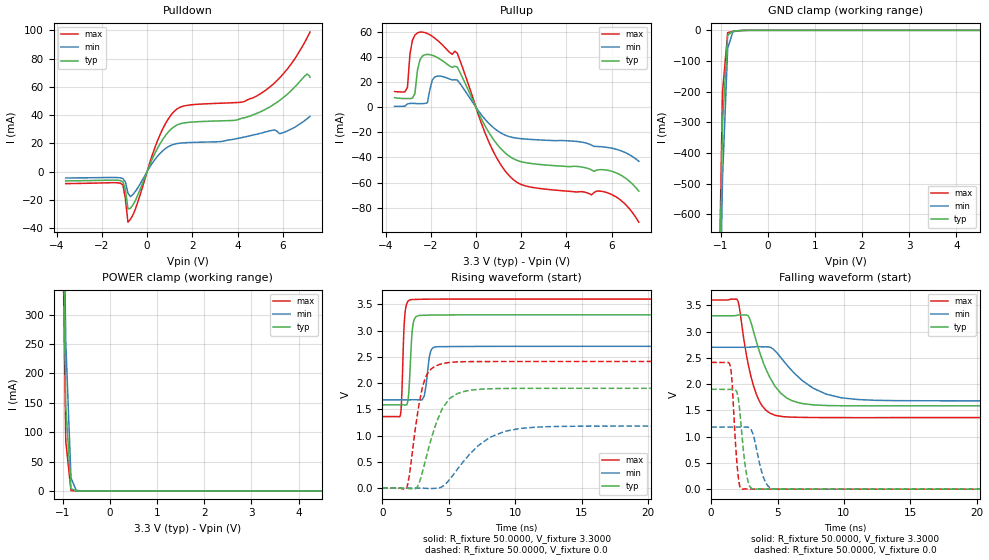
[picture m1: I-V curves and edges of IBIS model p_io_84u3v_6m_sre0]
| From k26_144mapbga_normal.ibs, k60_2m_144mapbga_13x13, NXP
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[Model] p_io_84u3v_6m_sre0
|   Model p_io_84u3v_6m_sre0
| Library cells for typ/min/max conditions are connected as defined below:
|  pad - External Pad
|  ipp_do - Core Input
|  ipp_obe - Output Buffer Enable
|  esd_boost - vdd_s_3v
|  esd_bus - vdd_s_3v
|  ipp_ina40a_3v - NC
|  ipp_ina40b_3v - NC
|  ipp_ina_3v - NC
|  ipp_ind - NC
|  ipp_ind_3v - NC
|  vdd_s_3v - vdd_s_3v
|  vdd_s_lv - vdd_s_lv
|  vss_bulk - vss_bulk
|  vss_s_lv - vss_s_lv
| All other pins connected to ground
Model_type I/O
Polarity   Non-Inverting
Enable   Active-High
Vinl =   1.1550V
Vinh =   2.3100V
Vmeas =  1.6500V
Cref =   25.0000pF
Rref =   50.0000
Vref =   0.0V
C_comp   2.2252pF   2.0533pF   2.4409pF
[Temperature Range]   25.0000   0.1250k   -40.0000
[Voltage Range]   3.3000V   2.7000V   3.6000V
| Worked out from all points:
|   slope of the pulldown table from 0 to 0.495 V, typ, clamps not added: 28.2 ohm
|   slope of the pullup table from 0 to 0.495 V, typ, clamps not added: 27.8 ohm
|   GND clamp passes 1 mA (typ) near -0.59 V on its own axis
|   POWER clamp passes 1 mA (typ) near -0.75 V on its own axis
|   rising waveform, R_fixture 50.0000, V_fixture 3.3000: 20-80 % time 221ps typ, 295ps min, 182ps max; typ from 1.58 V to 3.3 V
|   rising waveform, R_fixture 50.0000, V_fixture 0.0: 20-80 % time 1.43ns typ, 2.7ns min, 875ps max; typ from 0 V to 1.9 V
|   falling waveform, R_fixture 50.0000, V_fixture 3.3000: 20-80 % time 1.67ns typ, 2.73ns min, 1.11ns max; typ from 3.3 V to 1.58 V
|   falling waveform, R_fixture 50.0000, V_fixture 0.0: 20-80 % time 458ps typ, 665ps min, 346ps max; typ from 1.9 V to 0 V
[Pulldown]
|Voltage   I(typ)   I(min)   I(max)
-3.6V     -6.65mA    -4.6mA     -8.58mA
-1.18V    -6.454mA   -4.494mA   -8.311mA
-1.07V    -7.35mA    -5.056mA   -9.532mA
-960mV    -12.77mA   -7.464mA   -19.61mA
-850mV    -26.5mA    -15.32mA   -35.92mA
-520mV    -20.49mA   -14.14mA   -26.67mA
470mV     16.85mA    11.06mA    22.29mA
1.13V     31.02mA    19.04mA    41.5mA
4.87V     41.33mA    26.5mA     53.77mA
6.08V     53.2mA     27.9mA     70.3mA
7.07V     69.1mA     37.4mA     94.7mA
7.2V      66.9mA     39.2mA     98.8mA
[Pullup]
|Voltage   I(typ)   I(min)   I(max)
-3.6V     7.7mA      800uA      12.6mA
-3.03V    7mA        2.7mA      15.9mA
-2.92V    7mA        3.1mA      42.3mA
-2.7V     11.1mA     3.1mA      57.6mA
-2.48V    37.7mA     2.9mA      60mA
-2.04V    42.01mA    13.87mA    57.85mA
-1.82V    40.71mA    24.22mA    55.17mA
-830mV    32.18mA    21.79mA    43.24mA
600mV     -20.93mA   -13.37mA   -28.92mA
1.59V     -40.37mA   -23.95mA   -56.69mA
5.77V     -50.06mA   -31.89mA   -67.92mA
7.2V      -66.85mA   -43.01mA   -91.63mA
[GND_clamp]
|Voltage   I(typ)   I(min)   I(max)
-3.6V     -33.94A    -33.78A    -34.09A
-1.07V    -1.262A    -1.433A    -1.17A
-960mV    -306.5mA   -485.8mA   -202.7mA
-850mV    -15.64mA   -59.06mA   -7.665mA
-740mV    -3.056mA   -5.132mA   -3.462mA
-520mV    -339uA     -453.3uA   -280uA
7.2V      0A         0A         0A
[POWER_clamp]
|Voltage   I(typ)   I(min)   I(max)
-3.6V     23.18A     23.04A     23.31A
-1.05V    755.2mA    866.1mA    695.4mA
-940mV    144.8mA    253.6mA    84.13mA
-830mV    3.82mA     22.4mA     579uA
-720mV    53.91uA    987.1uA    2.438uA
-610mV    745.9nA    40.18uA    10.38nA
7.2V      0A         0A         0A
[Ramp]
| variable   typ   min   max
dV/dt_r  1.1402/1.4269n   0.7090/2.6951n   1.4470/0.8747n
dV/dt_f  1.0289/1.6700n   0.6111/2.7282n   1.3430/1.1080n
R_load = 50.0000
[Rising Waveform]
R_fixture= 50.0000
V_fixture= 3.3000
V_fixture_min= 2.7000
V_fixture_max= 3.6000
|time   V(typ)   V(min)   V(max)
0s        1.585V     1.681V     1.362V
1.347ns   1.586V     1.681V     1.375V
1.7ns     1.582V     1.681V     3.315V
1.932ns   1.667V     1.681V     3.558V
2.177ns   2.718V     1.682V     3.589V
2.4ns     3.211V     1.682V     3.592V
3.16ns    3.292V     1.755V     3.597V
3.62ns    3.295V     2.589V     3.598V
4.062ns   3.296V     2.691V     3.599V
50ns      3.3V       2.7V       3.6V
[Rising Waveform]
R_fixture= 50.0000
V_fixture= 0.0
V_fixture_min= 0.0
V_fixture_max= 0.0
|time   V(typ)   V(min)   V(max)
0s        2.183nV    162.4nV    4.475nV
1.818ns   -442.5uV   -83.4nV    -1.883mV
2.062ns   -11.58mV   -2.999uV   295.1mV
2.654ns   30.72mV    47.25uV    1.426V
3.227ns   509.2mV    -5.41mV    2.098V
4.637ns   1.56V      50.66mV    2.377V
5.665ns   1.802V     363.6mV    2.405V
7.239ns   1.879V     811.9mV    2.41V
10.38ns   1.899V     1.135V     2.411V
50ns      1.9V       1.182V     2.412V
[Falling Waveform]
R_fixture= 50.0000
V_fixture= 3.3000
V_fixture_min= 2.7000
V_fixture_max= 3.6000
|time   V(typ)   V(min)   V(max)
0s        3.3V       2.7V       3.6V
1.99ns    3.31V      2.7V       3.595V
2.801ns   3.293V     2.701V     2.365V
3.241ns   2.956V     2.709V     1.927V
3.837ns   2.474V     2.709V     1.586V
4.818ns   1.957V     2.631V     1.405V
6.068ns   1.686V     2.26V      1.37V
7.677ns   1.605V     1.923V     1.363V
11.03ns   1.586V     1.706V     1.361V
50ns      1.585V     1.681V     1.362V
[Falling Waveform]
R_fixture= 50.0000
V_fixture= 0.0
V_fixture_min= 0.0
V_fixture_max= 0.0
|time   V(typ)   V(min)   V(max)
0s        1.9V       1.182V     2.412V
1.448ns   1.901V     1.181V     2.335V
1.582ns   1.902V     1.181V     2.007V
1.969ns   1.816V     1.181V     415.6mV
2.321ns   1.012V     1.182V     155.7uV
2.563ns   445.8mV    1.183V     4.247mV
2.896ns   55.61mV    1.163V     1.666mV
3.923ns   1.361mV    237.8mV    552.1uV
4.616ns   801.9uV    9.969mV    178.5uV
50ns      13.25nV    178.1nV    11.32nV
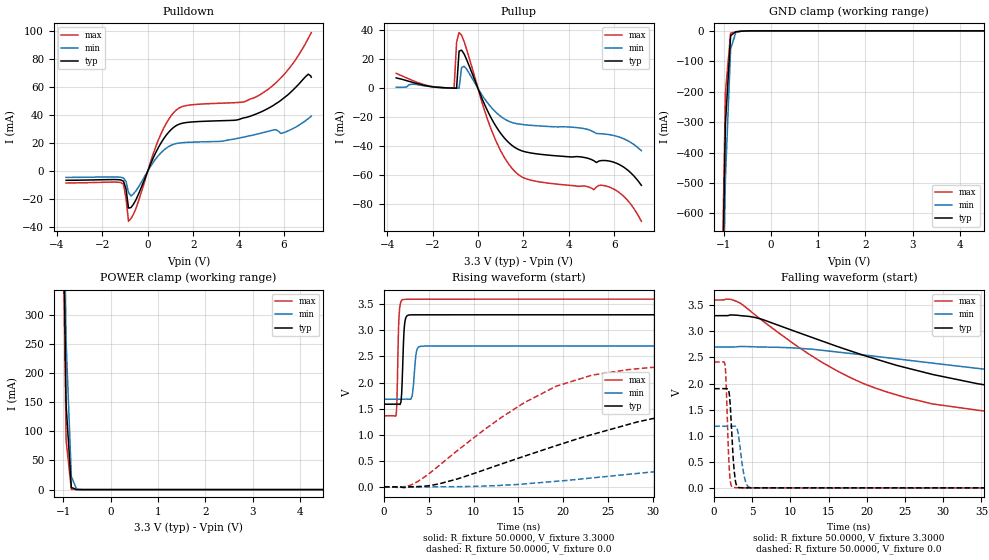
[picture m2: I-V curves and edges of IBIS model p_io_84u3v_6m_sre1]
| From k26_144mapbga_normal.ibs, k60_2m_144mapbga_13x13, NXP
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[Model] p_io_84u3v_6m_sre1
|   Model p_io_84u3v_6m_sre1
| Library cells for typ/min/max conditions are connected as defined below:
|  pad - External Pad
|  ipp_do - Core Input
|  ipp_obe - Output Buffer Enable
|  esd_boost - vdd_s_3v
|  esd_bus - vdd_s_3v
|  ipp_ina40a_3v - NC
|  ipp_ina40b_3v - NC
|  ipp_ina_3v - NC
|  ipp_ind - NC
|  ipp_ind_3v - NC
|  ipp_sre - vdd_s_lv
|  vdd_s_3v - vdd_s_3v
|  vdd_s_lv - vdd_s_lv
|  vss_bulk - vss_bulk
|  vss_s_lv - vss_s_lv
| All other pins connected to ground
Model_type I/O
Polarity   Non-Inverting
Enable   Active-High
Vinl =   1.1550V
Vinh =   2.3100V
Vmeas =  1.6500V
Cref =   25.0000pF
Rref =   50.0000
Vref =   0.0V
C_comp   2.2252pF   2.0533pF   2.4409pF
[Temperature Range]   25.0000   0.1250k   -40.0000
[Voltage Range]   3.3000V   2.7000V   3.6000V
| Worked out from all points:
|   slope of the pulldown table from 0 to 0.495 V, typ, clamps not added: 28.2 ohm
|   slope of the pullup table from 0 to 0.495 V, typ, clamps not added: 27.8 ohm
|   GND clamp passes 1 mA (typ) near -0.59 V on its own axis
|   POWER clamp passes 1 mA (typ) near -0.75 V on its own axis
|   rising waveform, R_fixture 50.0000, V_fixture 3.3000: 20-80 % time 220ps typ, 294ps min, 182ps max; typ from 1.58 V to 3.3 V
|   rising waveform, R_fixture 50.0000, V_fixture 0.0: 20-80 % time 23.9ns typ, 52.1ns min, 12.5ns max; typ from 0 V to 1.9 V
|   falling waveform, R_fixture 50.0000, V_fixture 3.3000: 20-80 % time 25.9ns typ, 44.9ns min, 16.5ns max; typ from 3.3 V to 1.58 V
|   falling waveform, R_fixture 50.0000, V_fixture 0.0: 20-80 % time 457ps typ, 664ps min, 346ps max; typ from 1.9 V to 0 V
[Pulldown]
|Voltage   I(typ)   I(min)   I(max)
-3.6V     -6.65mA    -4.6mA     -8.58mA
-1.18V    -6.454mA   -4.494mA   -8.311mA
-1.07V    -7.35mA    -5.056mA   -9.532mA
-960mV    -12.77mA   -7.464mA   -19.61mA
-850mV    -26.5mA    -15.32mA   -35.92mA
-520mV    -20.49mA   -14.14mA   -26.67mA
470mV     16.85mA    11.06mA    22.29mA
1.13V     31.02mA    19.04mA    41.5mA
4.87V     41.33mA    26.5mA     53.77mA
6.08V     53.2mA     27.9mA     70.3mA
7.07V     69.1mA     37.4mA     94.7mA
7.2V      66.9mA     39.2mA     98.8mA
[Pullup]
|Voltage   I(typ)   I(min)   I(max)
-3.6V     7.2mA      700uA      10.3mA
-1.05V    136uA      132uA      167uA
-940mV    114uA      95uA       31.74mA
-830mV    25.64mA    69.6uA     38.43mA
-720mV    26.3mA     14.39mA    36.55mA
-610mV    23.74mA    15.18mA    32.3mA
600mV     -20.93mA   -13.37mA   -28.92mA
1.59V     -40.37mA   -23.95mA   -56.69mA
2.69V     -45.35mA   -25.91mA   -64.42mA
5.77V     -50.07mA   -31.89mA   -67.92mA
6.54V     -55.64mA   -35.61mA   -76.28mA
7.2V      -66.86mA   -43.02mA   -91.64mA
[GND_clamp]
|Voltage   I(typ)   I(min)   I(max)
-3.6V     -33.94A    -33.78A    -34.09A
-1.07V    -1.262A    -1.433A    -1.17A
-960mV    -306.5mA   -485.8mA   -202.7mA
-850mV    -15.64mA   -59.06mA   -7.665mA
-740mV    -3.056mA   -5.132mA   -3.462mA
-520mV    -339uA     -453.3uA   -280uA
7.2V      0A         0A         0A
[POWER_clamp]
|Voltage   I(typ)   I(min)   I(max)
-3.6V     23.18A     23.04A     23.31A
-1.05V    755.2mA    866.1mA    695.4mA
-940mV    144.8mA    253.6mA    84.13mA
-830mV    3.82mA     22.4mA     579uA
-720mV    53.91uA    987.1uA    2.438uA
-610mV    745.9nA    40.18uA    10.38nA
7.2V      0A         0A         0A
[Ramp]
| variable   typ   min   max
dV/dt_r  1.1402/23.8601n   0.7089/52.0962n   1.4470/12.5479n
dV/dt_f  1.0289/25.9455n   0.6111/44.8713n   1.3430/16.4775n
R_load = 50.0000
[Rising Waveform]
R_fixture= 50.0000
V_fixture= 3.3000
V_fixture_min= 2.7000
V_fixture_max= 3.6000
|time   V(typ)   V(min)   V(max)
0s        1.585V     1.681V     1.362V
1.347ns   1.586V     1.681V     1.372V
1.664ns   1.584V     1.681V     3.201V
1.9ns     1.629V     1.681V     3.553V
2.26ns    3.036V     1.682V     3.594V
2.522ns   3.268V     1.683V     3.597V
3.159ns   3.299V     1.752V     3.599V
3.685ns   3.299V     2.631V     3.599V
4.358ns   3.299V     2.698V     3.599V
300ns     3.3V       2.7V       3.6V
[Rising Waveform]
R_fixture= 50.0000
V_fixture= 0.0
V_fixture_min= 0.0
V_fixture_max= 0.0
|time   V(typ)   V(min)   V(max)
0s        2.183nV    162.4nV    4.475nV
3.816ns   3.775mV    -6.726mV   105.4mV
13.11ns   438.3mV    28.78mV    1.331V
19.18ns   788mV      105.6mV    1.927V
23.21ns   1.002V     170.9mV    2.142V
33.95ns   1.455V     353.9mV    2.337V
45.12ns   1.716V     538.9mV    2.39V
56.42ns   1.819V     703.3mV    2.404V
104.2ns   1.897V     1.088V     2.411V
300ns     1.9V       1.181V     2.412V
[Falling Waveform]
R_fixture= 50.0000
V_fixture= 3.3000
V_fixture_min= 2.7000
V_fixture_max= 3.6000
|time   V(typ)   V(min)   V(max)
0s        3.3V       2.7V       3.6V
3.126ns   3.308V     2.707V     3.563V
6.243ns   3.232V     2.699V     3.214V
12.44ns   2.903V     2.661V     2.56V
21.06ns   2.474V     2.522V     1.915V
28.62ns   2.173V     2.39V      1.608V
42.48ns   1.825V     2.167V     1.406V
58.85ns   1.659V     1.96V      1.372V
100.7ns   1.589V     1.73V      1.362V
300ns     1.585V     1.681V     1.362V
[Falling Waveform]
R_fixture= 50.0000
V_fixture= 0.0
V_fixture_min= 0.0
V_fixture_max= 0.0
|time   V(typ)   V(min)   V(max)
0s        1.9V       1.182V     2.412V
1.443ns   1.901V     1.181V     2.341V
1.574ns   1.902V     1.181V     2.037V
1.926ns   1.86V      1.181V     538.9mV
2.22ns    1.308V     1.182V     50.93mV
2.561ns   448.6mV    1.183V     8.614mV
2.865ns   82.3mV     1.168V     2.727mV
4.034ns   543.9uV    167.1mV    572uV
5.095ns   325.6uV    1.641mV    389.9uV
300ns     3.763nV    167.7nV    5.446nV
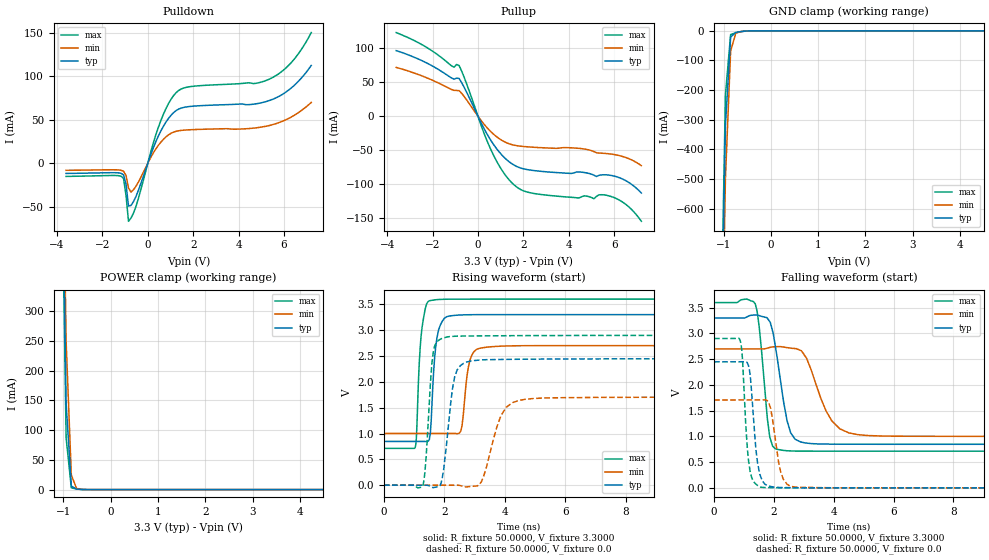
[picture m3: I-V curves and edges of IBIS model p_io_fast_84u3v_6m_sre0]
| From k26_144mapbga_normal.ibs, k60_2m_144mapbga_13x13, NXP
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[Model] p_io_fast_84u3v_6m_sre0
|   Model p_io_fast_84u3v_6m_sre0
| Library cells for typ/min/max conditions are connected as defined below:
|  pad - External Pad
|  ipp_do - Core Input
|  ipp_obe - Output Buffer Enable
|  esd_boost - vdd_s_3v
|  esd_bus - vdd_s_3v
|  ipp_ina40a_3v - NC
|  ipp_ina40b_3v - NC
|  ipp_ina_3v - NC
|  ipp_ind - NC
|  ipp_ind_3v - NC
|  vdd_s_3v - vdd_s_3v
|  vdd_s_lv - vdd_s_lv
|  vss_bulk - vss_bulk
|  vss_s_lv - vss_s_lv
| All other pins connected to ground
Model_type I/O
Polarity   Non-Inverting
Enable   Active-High
Vinl =   1.1550V
Vinh =   2.3100V
Vmeas =  1.6500V
Cref =   25.0000pF
Rref =   50.0000
Vref =   0.0V
C_comp   2.3650pF   2.1804pF   2.6055pF
[Temperature Range]   25.0000   0.1250k   -40.0000
[Voltage Range]   3.3000V   2.7000V   3.6000V
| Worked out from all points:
|   slope of the pulldown table from 0 to 0.495 V, typ, clamps not added: 15.1 ohm
|   slope of the pullup table from 0 to 0.495 V, typ, clamps not added: 15.7 ohm
|   GND clamp passes 1 mA (typ) near -0.54 V on its own axis
|   POWER clamp passes 1 mA (typ) near -0.72 V on its own axis
|   rising waveform, R_fixture 50.0000, V_fixture 3.3000: 20-80 % time 173ps typ, 202ps min, 156ps max; typ from 0.846 V to 3.3 V
|   rising waveform, R_fixture 50.0000, V_fixture 0.0: 20-80 % time 284ps typ, 509ps min, 181ps max; typ from 0 V to 2.45 V
|   falling waveform, R_fixture 50.0000, V_fixture 3.3000: 20-80 % time 397ps typ, 699ps min, 267ps max; typ from 3.3 V to 0.846 V
|   falling waveform, R_fixture 50.0000, V_fixture 0.0: 20-80 % time 210ps typ, 269ps min, 176ps max; typ from 2.45 V to 0 V
[Pulldown]
|Voltage   I(typ)   I(min)   I(max)
-3.6V     -11.79mA   -8.19mA    -15.19mA
-1.18V    -11.63mA   -8.126mA   -14.96mA
-1.07V    -13.43mA   -9.255mA   -17.42mA
-960mV    -23.9mA    -13.93mA   -36.84mA
-850mV    -49.3mA    -28.5mA    -66.79mA
-740mV    -48.6mA    -33.2mA    -63.07mA
-520mV    -38.21mA   -26.42mA   -49.68mA
470mV     31.47mA    20.68mA    41.56mA
1.24V     60.32mA    36.58mA    80.84mA
5.31V     71.6mA     43mA       96.08mA
6.3V      86mA       52.7mA     115mA
7.2V      112.3mA    69.9mA     150.1mA
[Pullup]
|Voltage   I(typ)   I(min)   I(max)
-3.6V     96.1mA     71.5mA     122.6mA
-2.37V    79.8mA     57.8mA     103.1mA
-1.05V    54.32mA    37.78mA    71.77mA
-830mV    55.31mA    37.44mA    74.3mA
600mV     -37.11mA   -23.72mA   -51.23mA
1.15V     -60.26mA   -37.2mA    -83.8mA
1.7V      -73.65mA   -43.23mA   -103.7mA
3.24V     -82.2mA    -46.92mA   -116.6mA
5.11V     -86.55mA   -51.96mA   -121mA
5.77V     -86.44mA   -55.19mA   -116.9mA
6.54V     -95.1mA    -60.97mA   -130mA
7.2V      -112.8mA   -72.54mA   -154.2mA
[GND_clamp]
|Voltage   I(typ)   I(min)   I(max)
-3.6V     -33.62A    -33.44A    -33.79A
-1.07V    -1.26A     -1.43A     -1.17A
-960mV    -319.6mA   -498.6mA   -216mA
-850mV    -20.96mA   -68.06mA   -12.76mA
-740mV    -5.527mA   -7.61mA    -6.376mA
-630mV    -2.448mA   -2.498mA   -2.679mA
-300mV    -2.556uA   -13.69uA   -557.5nA
7.2V      0A         0A         0A
[POWER_clamp]
|Voltage   I(typ)   I(min)   I(max)
-3.6V     21.5A      21.37A     21.62A
-1.05V    716.3mA    822.4mA    659.4mA
-940mV    144.5mA    248.6mA    86.77mA
-830mV    5.94mA     24.44mA    3.043mA
-720mV    938.4uA    1.98mA     905uA
-610mV    226.8uA    419.7uA    145.7uA
7.2V      0A         0A         0A
[Ramp]
| variable   typ   min   max
dV/dt_r  1.4689/0.2840n   1.0242/0.5093n   1.7410/0.1808n
dV/dt_f  1.4721/0.3970n   1.0197/0.6990n   1.7324/0.2668n
R_load = 50.0000
[Rising Waveform]
R_fixture= 50.0000
V_fixture= 3.3000
V_fixture_min= 2.7000
V_fixture_max= 3.6000
|time   V(typ)   V(min)   V(max)
0s        846.5mV    1V         712.6mV
1.032ns   846.5mV    1V         727.4mV
1.073ns   846.5mV    1V         907.3mV
1.229ns   846.6mV    1V         2.881V
1.505ns   888.7mV    1V         3.568V
1.765ns   2.88V      1V         3.591V
2.505ns   3.292V     1.011V     3.6V
2.91ns    3.299V     2.518V     3.6V
3.726ns   3.3V       2.686V     3.6V
50ns      3.3V       2.7V       3.6V
[Rising Waveform]
R_fixture= 50.0000
V_fixture= 0.0
V_fixture_min= 0.0
V_fixture_max= 0.0
|time   V(typ)   V(min)   V(max)
0s        2.058nV    189.8nV    3.201nV
1.285ns   -4.959uV   298.8nV    -13.86mV
1.628ns   -46.02mV   1.095uV    2.566V
1.93ns    133.4mV    -282nV     2.842V
2.202ns   1.545V     -7.886uV   2.877V
2.625ns   2.353V     -23.5mV    2.886V
3.221ns   2.424V     61.12mV    2.889V
4.046ns   2.434V     1.507V     2.893V
4.942ns   2.439V     1.677V     2.895V
50ns      2.448V     1.707V     2.902V
[Falling Waveform]
R_fixture= 50.0000
V_fixture= 3.3000
V_fixture_min= 2.7000
V_fixture_max= 3.6000
|time   V(typ)   V(min)   V(max)
0s        3.3V       2.7V       3.6V
1.379ns   3.36V      2.7V       3.572V
1.504ns   3.348V     2.7V       3.156V
1.861ns   3.23V      2.728V     991.7mV
2.43ns    1.339V     2.725V     720.8mV
2.71ns    943.8mV    2.707V     714.8mV
3.095ns   869.1mV    2.515V     713.5mV
3.939ns   848.6mV    1.299V     713.4mV
5.136ns   847.1mV    1.017V     712.8mV
50ns      846.5mV    1V         712.6mV
[Falling Waveform]
R_fixture= 50.0000
V_fixture= 0.0
V_fixture_min= 0.0
V_fixture_max= 0.0
|time   V(typ)   V(min)   V(max)
0s        2.448V     1.707V     2.902V
880.8ps   2.448V     1.707V     2.847V
954.6ps   2.448V     1.707V     2.457V
1.147ns   2.382V     1.707V     552.1mV
1.453ns   486.3mV    1.707V     47.02mV
1.657ns   102.7mV    1.71V      6.838mV
1.888ns   26.18mV    1.548V     4.392mV
2.313ns   5.734mV    170.8mV    465.3uV
2.802ns   1.323mV    12.27mV    117.7uV
50ns      9.282nV    202.8nV    7.374nV
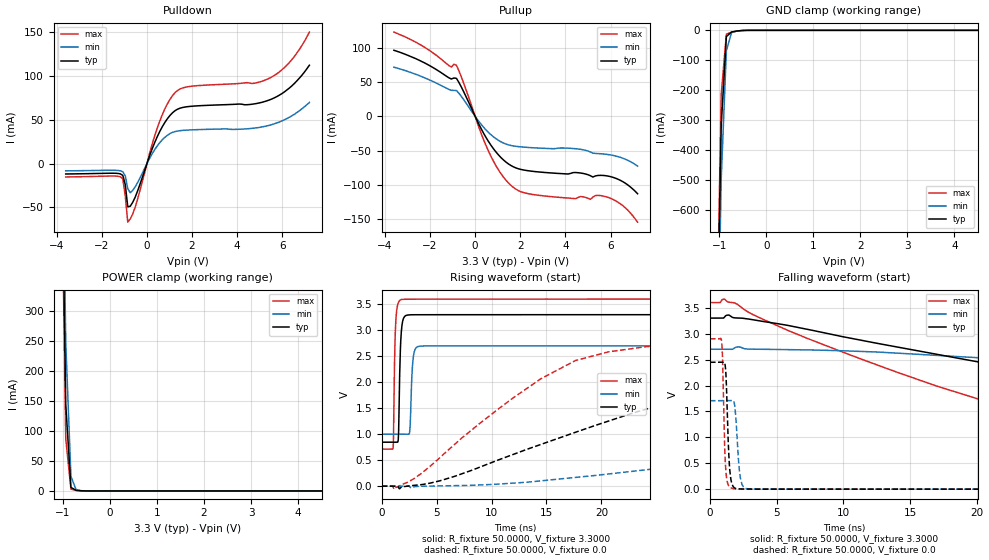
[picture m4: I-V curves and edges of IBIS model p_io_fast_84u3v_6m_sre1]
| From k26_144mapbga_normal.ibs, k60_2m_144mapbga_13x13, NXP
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[Model] p_io_fast_84u3v_6m_sre1
|   Model p_io_fast_84u3v_6m_sre1
| Library cells for typ/min/max conditions are connected as defined below:
|  pad - External Pad
|  ipp_do - Core Input
|  ipp_obe - Output Buffer Enable
|  esd_boost - vdd_s_3v
|  esd_bus - vdd_s_3v
|  ipp_ina40a_3v - NC
|  ipp_ina40b_3v - NC
|  ipp_ina_3v - NC
|  ipp_ind - NC
|  ipp_ind_3v - NC
|  ipp_sre - vdd_s_lv
|  vdd_s_3v - vdd_s_3v
|  vdd_s_lv - vdd_s_lv
|  vss_bulk - vss_bulk
|  vss_s_lv - vss_s_lv
| All other pins connected to ground
Model_type I/O
Polarity   Non-Inverting
Enable   Active-High
Vinl =   1.1550V
Vinh =   2.3100V
Vmeas =  1.6500V
Cref =   25.0000pF
Rref =   50.0000
Vref =   0.0V
C_comp   2.3650pF   2.1804pF   2.6055pF
[Temperature Range]   25.0000   0.1250k   -40.0000
[Voltage Range]   3.3000V   2.7000V   3.6000V
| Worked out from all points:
|   slope of the pulldown table from 0 to 0.495 V, typ, clamps not added: 15.1 ohm
|   slope of the pullup table from 0 to 0.495 V, typ, clamps not added: 15.7 ohm
|   GND clamp passes 1 mA (typ) near -0.54 V on its own axis
|   POWER clamp passes 1 mA (typ) near -0.72 V on its own axis
|   rising waveform, R_fixture 50.0000, V_fixture 3.3000: 20-80 % time 169ps typ, 198ps min, 153ps max; typ from 0.846 V to 3.3 V
|   rising waveform, R_fixture 50.0000, V_fixture 0.0: 20-80 % time 22.4ns typ, 53.7ns min, 11.3ns max; typ from 0 V to 2.45 V
|   falling waveform, R_fixture 50.0000, V_fixture 3.3000: 20-80 % time 37.1ns typ, 80ns min, 20.6ns max; typ from 3.3 V to 0.847 V
|   falling waveform, R_fixture 50.0000, V_fixture 0.0: 20-80 % time 212ps typ, 271ps min, 177ps max; typ from 2.45 V to 0 V
[Pulldown]
|Voltage   I(typ)   I(min)   I(max)
-3.6V     -11.79mA   -8.19mA    -15.19mA
-1.18V    -11.63mA   -8.126mA   -14.96mA
-1.07V    -13.43mA   -9.255mA   -17.42mA
-960mV    -23.9mA    -13.92mA   -36.84mA
-850mV    -49.3mA    -28.5mA    -66.79mA
-740mV    -48.6mA    -33.2mA    -63.07mA
-520mV    -38.21mA   -26.41mA   -49.68mA
470mV     31.47mA    20.68mA    41.56mA
1.24V     60.32mA    36.58mA    80.84mA
5.31V     71.6mA     43mA       96.08mA
6.3V      86mA       52.7mA     115mA
7.2V      112.3mA    69.9mA     150.1mA
[Pullup]
|Voltage   I(typ)   I(min)   I(max)
-3.6V     96.1mA     71.5mA     122.6mA
-2.37V    79.8mA     57.8mA     103.1mA
-1.05V    54.32mA    37.78mA    71.77mA
-830mV    55.31mA    37.44mA    74.3mA
600mV     -37.11mA   -23.72mA   -51.23mA
1.15V     -60.26mA   -37.2mA    -83.8mA
1.7V      -73.65mA   -43.23mA   -103.7mA
3.24V     -82.2mA    -46.92mA   -116.6mA
5.11V     -86.55mA   -51.96mA   -121mA
5.77V     -86.44mA   -55.19mA   -116.9mA
6.54V     -95.1mA    -60.97mA   -130mA
7.2V      -112.8mA   -72.54mA   -154.2mA
[GND_clamp]
|Voltage   I(typ)   I(min)   I(max)
-3.6V     -33.62A    -33.44A    -33.79A
-1.07V    -1.26A     -1.43A     -1.17A
-960mV    -319.6mA   -498.6mA   -216mA
-850mV    -20.96mA   -68.06mA   -12.76mA
-740mV    -5.527mA   -7.61mA    -6.376mA
-630mV    -2.448mA   -2.498mA   -2.679mA
-300mV    -2.556uA   -13.69uA   -557.5nA
7.2V      0A         0A         0A
[POWER_clamp]
|Voltage   I(typ)   I(min)   I(max)
-3.6V     21.5A      21.37A     21.62A
-1.05V    716.3mA    822.4mA    659.4mA
-940mV    144.5mA    248.6mA    86.77mA
-830mV    5.94mA     24.44mA    3.043mA
-720mV    938.4uA    1.98mA     905uA
-610mV    226.8uA    419.7uA    145.7uA
7.2V      0A         0A         0A
[Ramp]
| variable   typ   min   max
dV/dt_r  1.4689/22.4023n   1.0237/53.6982n   1.7410/11.3248n
dV/dt_f  1.4720/37.1234n   1.0158/80.0239n   1.7324/20.5763n
R_load = 50.0000
[Rising Waveform]
R_fixture= 50.0000
V_fixture= 3.3000
V_fixture_min= 2.7000
V_fixture_max= 3.6000
|time   V(typ)   V(min)   V(max)
0s        846.5mV    1V         712.6mV
1.031ns   846.5mV    1V         727mV
1.224ns   846.6mV    1V         2.888V
1.504ns   888.9mV    1V         3.524V
1.694ns   2.603V     1V         3.583V
1.961ns   3.215V     1V         3.596V
2.556ns   3.297V     1.065V     3.597V
2.968ns   3.298V     2.59V      3.598V
3.853ns   3.299V     2.698V     3.598V
300ns     3.3V       2.7V       3.6V
[Rising Waveform]
R_fixture= 50.0000
V_fixture= 0.0
V_fixture_min= 0.0
V_fixture_max= 0.0
|time   V(typ)   V(min)   V(max)
0s        2.058nV    189.8nV    3.201nV
1.13ns    -1.195uV   220.1nV    -57.72mV
3.067ns   16.76mV    -7.304mV   163.8mV
11.99ns   613.2mV    58.92mV    1.702V
17.65ns   1.038V     168.6mV    2.418V
24.03ns   1.479V     315.1mV    2.683V
33.46ns   1.988V     530.6mV    2.81V
55.18ns   2.332V     997.5mV    2.887V
97.43ns   2.435V     1.525V     2.901V
300ns     2.448V     1.706V     2.902V
[Falling Waveform]
R_fixture= 50.0000
V_fixture= 3.3000
V_fixture_min= 2.7000
V_fixture_max= 3.6000
|time   V(typ)   V(min)   V(max)
0s        3.3V       2.7V       3.6V
1.066ns   3.312V     2.7V       3.668V
9.779ns   2.951V     2.672V     2.661V
23.09ns   2.316V     2.489V     1.499V
30.33ns   1.996V     2.377V     1.091V
44.08ns   1.509V     2.16V      831.9mV
66.38ns   1.048V     1.829V     741.2mV
81.38ns   948.3mV    1.637V     724.2mV
143.2ns   856.2mV    1.167V     713.3mV
300ns     846.6mV    1.007V     712.6mV
[Falling Waveform]
R_fixture= 50.0000
V_fixture= 0.0
V_fixture_min= 0.0
V_fixture_max= 0.0
|time   V(typ)   V(min)   V(max)
0s        2.448V     1.707V     2.902V
872.4ps   2.448V     1.707V     2.861V
956.1ps   2.447V     1.707V     2.42V
1.137ns   2.398V     1.707V     605.5mV
1.283ns   1.629V     1.707V     157.6mV
1.481ns   382.2mV    1.707V     41.89mV
1.92ns    15.4mV     1.456V     3.715mV
2.279ns   3.545mV    217mV      1.781mV
3.151ns   954.3uV    2.283mV    847.1uV
300ns     691.3nV    -1.111uV   3.674nV
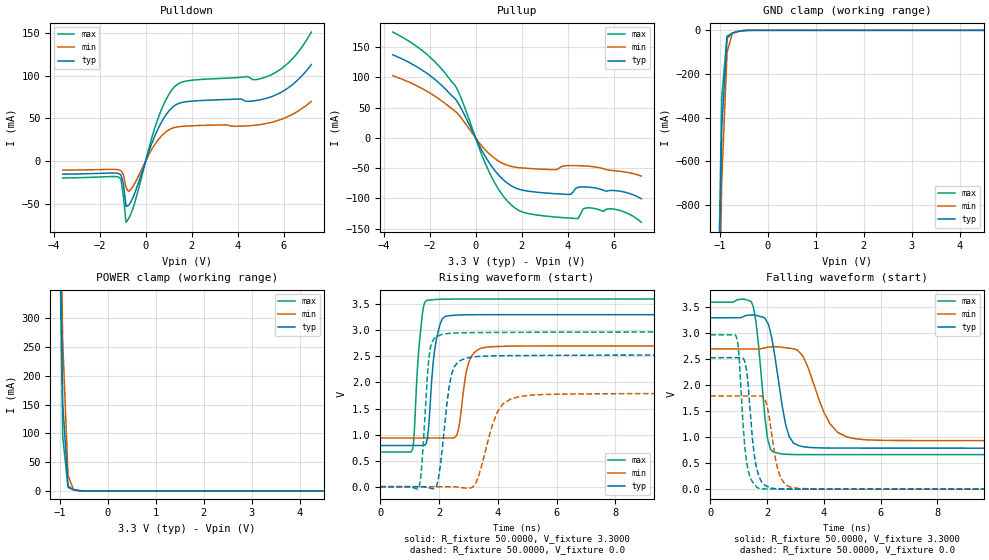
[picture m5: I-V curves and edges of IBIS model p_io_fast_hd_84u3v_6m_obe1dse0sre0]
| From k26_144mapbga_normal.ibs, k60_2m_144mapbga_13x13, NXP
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[Model] p_io_fast_hd_84u3v_6m_obe1dse0sre0
|   Model p_io_fast_hd_84u3v_6m_obe1dse0sre0
| Library cells for typ/min/max conditions are connected as defined below:
|  pad - External Pad
|  ipp_do - Core Input
|  ipp_obe - Output Buffer Enable
|  esd_boost - vdd_s_3v
|  esd_bus - vdd_s_3v
|  ipp_ina40a_3v - NC
|  ipp_ina40b_3v - NC
|  ipp_ina_3v - NC
|  ipp_ind - NC
|  ipp_ind_3v - NC
|  vdd_s_3v - vdd_s_3v
|  vdd_s_lv - vdd_s_lv
|  vss_bulk - vss_bulk
|  vss_s_lv - vss_s_lv
| All other pins connected to ground
Model_type I/O
Polarity   Non-Inverting
Enable   Active-High
Vinl =   1.1550V
Vinh =   2.3100V
Vmeas =  1.6500V
Cref =   25.0000pF
Rref =   50.0000
Vref =   0.0V
C_comp   3.1155pF   2.8752pF   3.4328pF
[Temperature Range]   25.0000   0.1250k   -40.0000
[Voltage Range]   3.3000V   2.7000V   3.6000V
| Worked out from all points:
|   slope of the pulldown table from 0 to 0.495 V, typ, clamps not added: 14.1 ohm
|   slope of the pullup table from 0 to 0.495 V, typ, clamps not added: 14.1 ohm
|   GND clamp passes 1 mA (typ) near -0.49 V on its own axis
|   POWER clamp passes 1 mA (typ) near -0.65 V on its own axis
|   rising waveform, R_fixture 50.0000, V_fixture 3.3000: 20-80 % time 238ps typ, 278ps min, 200ps max; typ from 0.79 V to 3.3 V
|   rising waveform, R_fixture 50.0000, V_fixture 0.0: 20-80 % time 316ps typ, 563ps min, 204ps max; typ from 0 V to 2.53 V
|   falling waveform, R_fixture 50.0000, V_fixture 3.3000: 20-80 % time 436ps typ, 748ps min, 302ps max; typ from 3.3 V to 0.79 V
|   falling waveform, R_fixture 50.0000, V_fixture 0.0: 20-80 % time 266ps typ, 330ps min, 227ps max; typ from 2.53 V to 0 V
[Pulldown]
|Voltage   I(typ)   I(min)   I(max)
-3.6V     -15.22mA   -10.51mA   -19.67mA
-1.18V    -14.33mA   -9.944mA   -18.52mA
-1.07V    -16.06mA   -11.02mA   -20.93mA
-960mV    -27.25mA   -15.95mA   -41.78mA
-850mV    -52.91mA   -30.92mA   -71.44mA
-520mV    -40.9mA    -28.31mA   -53.14mA
580mV     39.96mA    26.07mA    52.81mA
1.24V     64.67mA    39.27mA    86.6mA
2.01V     70.27mA    41.42mA    94.74mA
5.31V     74.08mA    44.5mA     99.37mA
6.3V      87.9mA     53.7mA     117.6mA
7.2V      113.1mA    70mA       151.1mA
[Pullup]
|Voltage   I(typ)   I(min)   I(max)
-3.6V     137.4mA    102.8mA    174.9mA
-2.15V    107.7mA    77.89mA    139.2mA
-940mV    66.65mA    45.7mA     89.33mA
-610mV    47.59mA    32.36mA    64.09mA
600mV     -41.43mA   -26.49mA   -57.18mA
1.15V     -67.21mA   -41.51mA   -93.44mA
1.7V      -82.09mA   -48.21mA   -115.5mA
4.12V     -93.45mA   -45.73mA   -132.6mA
4.45V     -81.68mA   -45.9mA    -133.4mA
4.78V     -81.1mA    -46.45mA   -115.8mA
5.88V     -86.86mA   -53.69mA   -117.1mA
7.2V      -100.6mA   -63.06mA   -139.3mA
[GND_clamp]
|Voltage   I(typ)   I(min)   I(max)
-3.6V     -50.08A    -49.79A    -50.34A
-1.07V    -1.779A    -2.002A    -1.667A
-960mV    -443.3mA   -682.5mA   -306.2mA
-850mV    -35.9mA    -100mA     -25.86mA
-740mV    -11.78mA   -14.19mA   -13.74mA
-630mV    -5.294mA   -5.309mA   -5.801mA
-520mV    -1.368mA   -1.815mA   -1.132mA
-300mV    -5.607uA   -29.91uA   -1.227uA
7.2V      0A         0A         0A
[POWER_clamp]
|Voltage   I(typ)   I(min)   I(max)
-3.6V     22.91A     22.74A     23.08A
-1.05V    756.1mA    864.1mA    699.9mA
-940mV    152mA      258.6mA    93.81mA
-830mV    8.474mA    26.71mA    6.073mA
-720mV    2.026mA    3.175mA    2.02mA
-610mV    503.6uA    883.5uA    324uA
-390mV    4.632uA    38.32uA    661.9nA
7.2V      0A         0A         0A
[Ramp]
| variable   typ   min   max
dV/dt_r  1.5181/0.3157n   1.0768/0.5628n   1.7829/0.2039n
dV/dt_f  1.5061/0.4364n   1.0595/0.7479n   1.7611/0.3020n
R_load = 50.0000
[Rising Waveform]
R_fixture= 50.0000
V_fixture= 3.3000
V_fixture_min= 2.7000
V_fixture_max= 3.6000
|time   V(typ)   V(min)   V(max)
0s        789.9mV    934.2mV    664.8mV
1.103ns   789.9mV    934.2mV    734.4mV
1.413ns   789.9mV    934.2mV    3.229V
1.629ns   1.056V     934.2mV    3.58V
1.805ns   2.41V      934.2mV    3.588V
1.966ns   2.973V     934.2mV    3.595V
2.488ns   3.288V     937.4mV    3.599V
3.025ns   3.298V     2.411V     3.6V
3.744ns   3.3V       2.683V     3.6V
50ns      3.3V       2.7V       3.6V
[Rising Waveform]
R_fixture= 50.0000
V_fixture= 0.0
V_fixture_min= 0.0
V_fixture_max= 0.0
|time   V(typ)   V(min)   V(max)
0s        3.824nV    401.8nV    4.302nV
1.296ns   -5.633uV   540.7nV    -37.48mV
1.413ns   255.2uV    767.7nV    416.4mV
1.701ns   -29.28mV   1.115uV    2.658V
1.977ns   156.8mV    -2.068uV   2.896V
2.364ns   1.98V      181.8uV    2.944V
3.2ns     2.492V     22.97mV    2.957V
3.985ns   2.512V     1.434V     2.96V
5.209ns   2.518V     1.759V     2.963V
50ns      2.53V      1.795V     2.971V
[Falling Waveform]
R_fixture= 50.0000
V_fixture= 3.3000
V_fixture_min= 2.7000
V_fixture_max= 3.6000
|time   V(typ)   V(min)   V(max)
0s        3.3V       2.7V       3.6V
1.448ns   3.354V     2.7V       3.606V
1.619ns   3.345V     2.699V     3.175V
2.017ns   3.203V     2.734V     970.6mV
2.569ns   1.494V     2.728V     675.4mV
2.783ns   1.005V     2.714V     668.7mV
3.112ns   838.3mV    2.654V     665.7mV
4.218ns   792mV      1.257V     665mV
5.452ns   790.4mV    952mV      664.8mV
50ns      789.9mV    934.2mV    664.8mV
[Falling Waveform]
R_fixture= 50.0000
V_fixture= 0.0
V_fixture_min= 0.0
V_fixture_max= 0.0
|time   V(typ)   V(min)   V(max)
0s        2.53V      1.795V     2.971V
930.5ps   2.53V      1.795V     2.914V
1.018ns   2.53V      1.795V     2.531V
1.188ns   2.495V     1.795V     1.005V
1.32ns    2.075V     1.795V     396.9mV
1.545ns   675.2mV    1.794V     98.02mV
1.832ns   126.8mV    1.787V     5.288mV
2.479ns   5.946mV    219.9mV    639.8uV
3.044ns   1.346mV    17.97mV    18.7uV
50ns      9.986nV    412.7nV    8.007nV
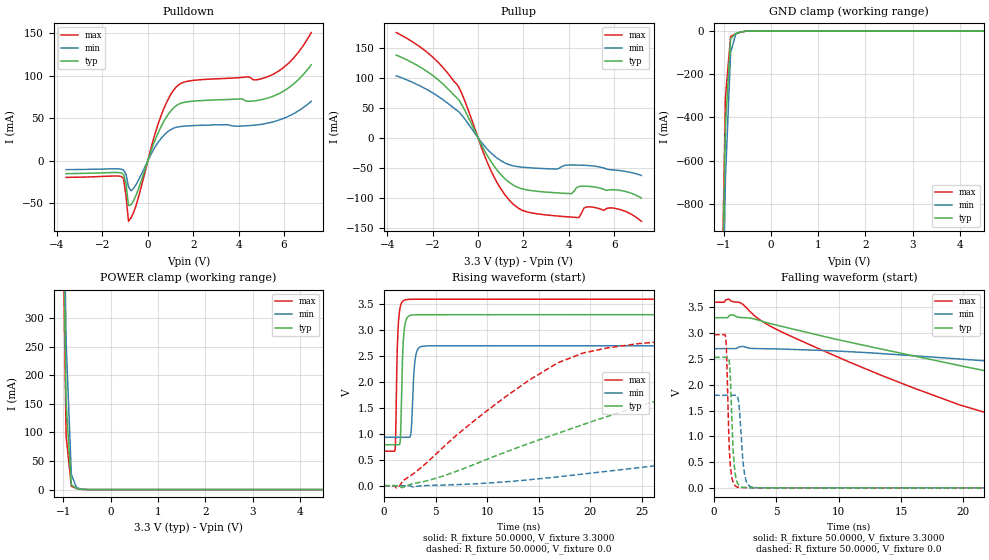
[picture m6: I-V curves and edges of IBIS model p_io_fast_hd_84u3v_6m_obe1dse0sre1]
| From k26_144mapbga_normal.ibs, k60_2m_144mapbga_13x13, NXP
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[Model] p_io_fast_hd_84u3v_6m_obe1dse0sre1
|   Model p_io_fast_hd_84u3v_6m_obe1dse0sre1
| Library cells for typ/min/max conditions are connected as defined below:
|  pad - External Pad
|  ipp_do - Core Input
|  ipp_obe - Output Buffer Enable
|  esd_boost - vdd_s_3v
|  esd_bus - vdd_s_3v
|  ipp_ina40a_3v - NC
|  ipp_ina40b_3v - NC
|  ipp_ina_3v - NC
|  ipp_ind - NC
|  ipp_ind_3v - NC
|  ipp_sre - vdd_s_lv
|  vdd_s_3v - vdd_s_3v
|  vdd_s_lv - vdd_s_lv
|  vss_bulk - vss_bulk
|  vss_s_lv - vss_s_lv
| All other pins connected to ground
Model_type I/O
Polarity   Non-Inverting
Enable   Active-High
Vinl =   1.1550V
Vinh =   2.3100V
Vmeas =  1.6500V
Cref =   25.0000pF
Rref =   50.0000
Vref =   0.0V
C_comp   3.1155pF   2.8752pF   3.4328pF
[Temperature Range]   25.0000   0.1250k   -40.0000
[Voltage Range]   3.3000V   2.7000V   3.6000V
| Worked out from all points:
|   slope of the pulldown table from 0 to 0.495 V, typ, clamps not added: 14.1 ohm
|   slope of the pullup table from 0 to 0.495 V, typ, clamps not added: 14.1 ohm
|   GND clamp passes 1 mA (typ) near -0.49 V on its own axis
|   POWER clamp passes 1 mA (typ) near -0.65 V on its own axis
|   rising waveform, R_fixture 50.0000, V_fixture 3.3000: 20-80 % time 227ps typ, 266ps min, 202ps max; typ from 0.79 V to 3.3 V
|   rising waveform, R_fixture 50.0000, V_fixture 0.0: 20-80 % time 24.6ns typ, 58.9ns min, 12ns max; typ from 0 V to 2.53 V
|   falling waveform, R_fixture 50.0000, V_fixture 3.3000: 20-80 % time 34.9ns typ, 76.4ns min, 19.1ns max; typ from 3.3 V to 0.79 V
|   falling waveform, R_fixture 50.0000, V_fixture 0.0: 20-80 % time 265ps typ, 334ps min, 227ps max; typ from 2.53 V to 0 V
[Pulldown]
|Voltage   I(typ)   I(min)   I(max)
-3.6V     -15.22mA   -10.51mA   -19.67mA
-1.18V    -14.33mA   -9.944mA   -18.52mA
-1.07V    -16.06mA   -11.02mA   -20.93mA
-960mV    -27.25mA   -15.95mA   -41.78mA
-850mV    -52.91mA   -30.92mA   -71.44mA
-520mV    -40.9mA    -28.31mA   -53.14mA
580mV     39.96mA    26.07mA    52.81mA
1.24V     64.67mA    39.27mA    86.6mA
2.01V     70.27mA    41.42mA    94.74mA
5.31V     74.08mA    44.5mA     99.37mA
6.3V      87.9mA     53.7mA     117.6mA
7.2V      113.1mA    70mA       151.1mA
[Pullup]
|Voltage   I(typ)   I(min)   I(max)
-3.6V     137.4mA    102.8mA    174.9mA
-2.15V    107.7mA    77.89mA    139.2mA
-940mV    66.65mA    45.7mA     89.33mA
-610mV    47.59mA    32.36mA    64.09mA
600mV     -41.43mA   -26.49mA   -57.18mA
1.15V     -67.21mA   -41.51mA   -93.44mA
1.7V      -82.09mA   -48.21mA   -115.5mA
4.12V     -93.45mA   -45.75mA   -132.6mA
4.45V     -81.7mA    -45.93mA   -133.4mA
4.78V     -81.14mA   -46.5mA    -115.8mA
5.99V     -87.03mA   -54.1mA    -117.7mA
7.2V      -100.8mA   -63.19mA   -139.6mA
[GND_clamp]
|Voltage   I(typ)   I(min)   I(max)
-3.6V     -50.08A    -49.79A    -50.34A
-1.07V    -1.779A    -2.002A    -1.667A
-960mV    -443.3mA   -682.5mA   -306.2mA
-850mV    -35.9mA    -100mA     -25.86mA
-740mV    -11.78mA   -14.19mA   -13.74mA
-630mV    -5.294mA   -5.309mA   -5.801mA
-520mV    -1.368mA   -1.815mA   -1.132mA
-300mV    -5.607uA   -29.91uA   -1.227uA
7.2V      0A         0A         0A
[POWER_clamp]
|Voltage   I(typ)   I(min)   I(max)
-3.6V     22.91A     22.74A     23.08A
-1.05V    756.1mA    864.1mA    699.9mA
-940mV    152mA      258.6mA    93.81mA
-830mV    8.474mA    26.71mA    6.073mA
-720mV    2.026mA    3.175mA    2.02mA
-610mV    503.6uA    883.5uA    324uA
-390mV    4.632uA    38.32uA    661.9nA
7.2V      0A         0A         0A
[Ramp]
| variable   typ   min   max
dV/dt_r  1.5181/24.5516n   1.0757/58.8656n   1.7829/11.9587n
dV/dt_f  1.5060/34.8928n   1.0563/76.4264n   1.7611/19.1493n
R_load = 50.0000
[Rising Waveform]
R_fixture= 50.0000
V_fixture= 3.3000
V_fixture_min= 2.7000
V_fixture_max= 3.6000
|time   V(typ)   V(min)   V(max)
0s        789.9mV    934.3mV    664.8mV
1.076ns   789.9mV    934.3mV    692.4mV
1.303ns   789.9mV    934.3mV    2.713V
1.557ns   829.1mV    934.3mV    3.43V
1.868ns   2.763V     934.3mV    3.569V
2.426ns   3.277V     933.9mV    3.595V
2.65ns    3.292V     1.082V     3.597V
3.071ns   3.298V     2.502V     3.598V
4.262ns   3.299V     2.698V     3.598V
300ns     3.3V       2.7V       3.6V
[Rising Waveform]
R_fixture= 50.0000
V_fixture= 0.0
V_fixture_min= 0.0
V_fixture_max= 0.0
|time   V(typ)   V(min)   V(max)
0s        3.824nV    401.9nV    4.302nV
1.427ns   245.4uV    817.8nV    -24.63mV
10.04ns   515.3mV    50.44mV    1.456V
16.81ns   1.008V     168.9mV    2.369V
21.59ns   1.333V     278.3mV    2.658V
29.88ns   1.835V     462.4mV    2.825V
37.24ns   2.138V     620.8mV    2.886V
54.67ns   2.381V     977.1mV    2.949V
107.6ns   2.517V     1.617V     2.971V
300ns     2.53V      1.793V     2.971V
[Falling Waveform]
R_fixture= 50.0000
V_fixture= 3.3000
V_fixture_min= 2.7000
V_fixture_max= 3.6000
|time   V(typ)   V(min)   V(max)
0s        3.3V       2.7V       3.6V
2.095ns   3.305V     2.739V     3.591V
4.51ns    3.186V     2.698V     3.136V
10.99ns   2.819V     2.64V      2.426V
25.75ns   2.078V     2.396V     1.175V
39.14ns   1.517V     2.169V     807.9mV
60.93ns   1.008V     1.813V     701mV
98.6ns    834.4mV    1.344V     669.1mV
128.6ns   804.1mV    1.134V     666mV
300ns     790mV      939.5mV    664.8mV
[Falling Waveform]
R_fixture= 50.0000
V_fixture= 0.0
V_fixture_min= 0.0
V_fixture_max= 0.0
|time   V(typ)   V(min)   V(max)
0s        2.53V      1.795V     2.971V
918.3ps   2.53V      1.795V     2.931V
1.181ns   2.502V     1.795V     1.019V
1.314ns   2.102V     1.795V     405.4mV
1.594ns   494.6mV    1.794V     75.18mV
1.966ns   56.31mV    1.679V     8.713mV
2.179ns   19.47mV    994.1mV    4.741mV
2.584ns   4.539mV    125mV      4.393mV
3.76ns    930.4uV    1.988mV    740uV
300ns     17.15nV    889.2nV    4.789nV
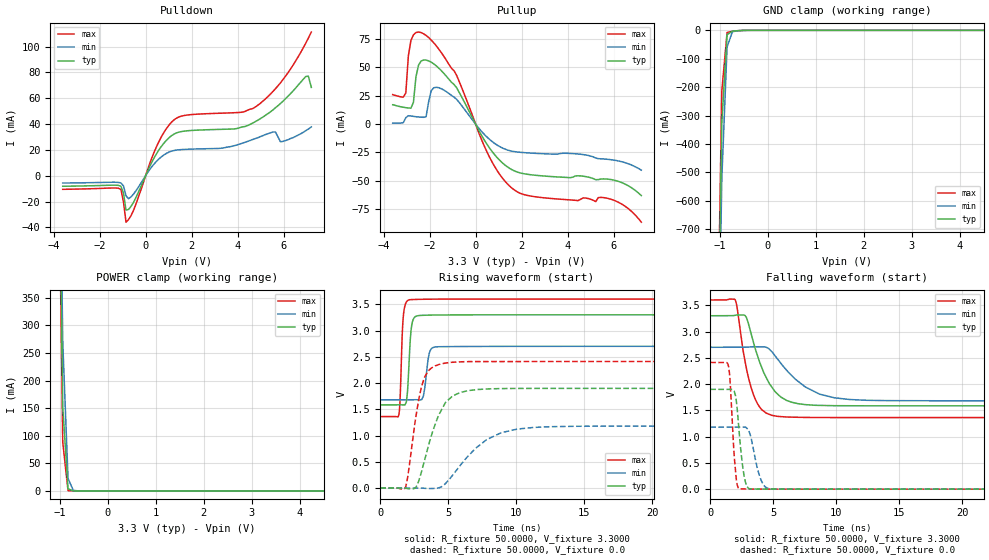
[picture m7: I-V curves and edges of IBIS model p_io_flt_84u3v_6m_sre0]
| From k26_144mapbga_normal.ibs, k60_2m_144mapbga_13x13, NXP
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[Model] p_io_flt_84u3v_6m_sre0
|   Model p_io_flt_84u3v_6m_sre0
| Library cells for typ/min/max conditions are connected as defined below:
|  pad - External Pad
|  ipp_do - Core Input
|  ipp_obe - Output Buffer Enable
|  esd_boost - vdd_s_3v
|  esd_bus - vdd_s_3v
|  ipp_do_3v - vss_bulk
|  ipp_ibe - vss_s_lv
|  ipp_ibe_3v - vss_bulk
|  ipp_ina40a_3v - NC
|  ipp_ina40b_3v - NC
|  ipp_ina_3v - NC
|  ipp_ind - NC
|  ipp_ind_3v - NC
|  ipp_obe1_3v - vss_bulk
|  ipp_pue - vss_s_lv
|  ipp_pue_3v - vss_bulk
|  ipp_pus - vss_s_lv
|  ipp_pus_3v - vss_bulk
|  ipp_sre - vss_s_lv
|  ipp_sre_3v - vss_bulk
|  ipt_mode_sw_3v - vss_bulk
|  vdd_s_3v - vdd_s_3v
|  vdd_s_lv - vdd_s_lv
|  vss_bulk - vss_bulk
|  vss_s_lv - vss_s_lv
| All other pins connected to ground
Model_type I/O
Polarity   Non-Inverting
Enable   Active-High
Vinl =   1.1550V
Vinh =   2.3100V
Vmeas =  1.6500V
Cref =   25.0000pF
Rref =   50.0000
Vref =   0.0V
C_comp   2.2909pF   2.1249pF   2.5080pF
[Temperature Range]   25.0000   0.1250k   -40.0000
[Voltage Range]   3.3000V   2.7000V   3.6000V
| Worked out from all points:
|   slope of the pulldown table from 0 to 0.495 V, typ, clamps not added: 28.2 ohm
|   slope of the pullup table from 0 to 0.495 V, typ, clamps not added: 27.8 ohm
|   GND clamp passes 1 mA (typ) near -0.59 V on its own axis
|   POWER clamp passes 1 mA (typ) near -0.75 V on its own axis
|   rising waveform, R_fixture 50.0000, V_fixture 3.3000: 20-80 % time 224ps typ, 291ps min, 185ps max; typ from 1.58 V to 3.3 V
|   rising waveform, R_fixture 50.0000, V_fixture 0.0: 20-80 % time 1.46ns typ, 2.71ns min, 867ps max; typ from 0 V to 1.9 V
|   falling waveform, R_fixture 50.0000, V_fixture 3.3000: 20-80 % time 1.68ns typ, 2.76ns min, 1.11ns max; typ from 3.3 V to 1.59 V
|   falling waveform, R_fixture 50.0000, V_fixture 0.0: 20-80 % time 462ps typ, 668ps min, 346ps max; typ from 1.9 V to 0 V
[Pulldown]
|Voltage   I(typ)   I(min)   I(max)
-3.6V     -8.15mA    -5.66mA    -10.53mA
-1.07V    -8.198mA   -5.617mA   -10.68mA
-850mV    -26.62mA   -15.53mA   -35.97mA
-520mV    -20.5mA    -14.15mA   -26.68mA
470mV     16.86mA    11.06mA    22.3mA
1.13V     31.02mA    19.05mA    41.52mA
4.76V     41.79mA    28.7mA     53.11mA
5.64V     52.6mA     33.9mA     67.3mA
5.86V     55.9mA     26.3mA     71.9mA
6.96V     76.8mA     34.9mA     102.7mA
7.07V     77.1mA     36.1mA     106.5mA
7.2V      68.4mA     37.8mA     111.2mA
[Pullup]
|Voltage   I(typ)   I(min)   I(max)
-3.6V     17.1mA     900uA      26mA
-3.03V    14.5mA     5.7mA      27.6mA
-2.81V    14.1mA     7.2mA      73.8mA
-2.48V    51.9mA     6.3mA      81.2mA
-2.26V    56.6mA     6mA        79.7mA
-1.93V    54.69mA    29.29mA    74.23mA
-1.6V     49.42mA    32.12mA    66.23mA
-830mV    32.27mA    22.03mA    43.28mA
710mV     -23.99mA   -15.23mA   -33.19mA
1.59V     -40.35mA   -23.94mA   -56.67mA
5.77V     -48.61mA   -31.15mA   -65.69mA
7.2V      -63.09mA   -40.64mA   -86.56mA
[GND_clamp]
|Voltage   I(typ)   I(min)   I(max)
-3.6V     -40.71A    -40.48A    -40.9A
-1.07V    -1.446A    -1.633A    -1.35A
-960mV    -327.7mA   -524.2mA   -214.8mA
-850mV    -15.52mA   -59.01mA   -7.646mA
-740mV    -3.054mA   -5.095mA   -3.462mA
-520mV    -339uA     -453.3uA   -279.9uA
7.2V      0A         0A         0A
[POWER_clamp]
|Voltage   I(typ)   I(min)   I(max)
-3.6V     26.65A     26.49A     26.81A
-1.05V    840.8mA    960.6mA    777.3mA
-940mV    152.6mA    269.8mA    87.83mA
-830mV    3.854mA    22.63mA    588.6uA
-720mV    55.07uA    1mA        2.492uA
-610mV    762.6nA    41.04uA    10.61nA
7.2V      0A         0A         0A
[Ramp]
| variable   typ   min   max
dV/dt_r  1.1397/1.4643n   0.7086/2.7130n   1.4466/0.8675n
dV/dt_f  1.0286/1.6823n   0.6109/2.7547n   1.3427/1.1085n
R_load = 50.0000
[Rising Waveform]
R_fixture= 50.0000
V_fixture= 3.3000
V_fixture_min= 2.7000
V_fixture_max= 3.6000
|time   V(typ)   V(min)   V(max)
0s        1.585V     1.681V     1.361V
1.367ns   1.585V     1.681V     1.393V
1.688ns   1.584V     1.681V     3.253V
1.919ns   1.643V     1.681V     3.543V
2.145ns   2.533V     1.682V     3.587V
2.483ns   3.241V     1.682V     3.591V
3.175ns   3.291V     1.756V     3.596V
3.598ns   3.294V     2.561V     3.597V
4.174ns   3.296V     2.691V     3.598V
50ns      3.3V       2.7V       3.6V
[Rising Waveform]
R_fixture= 50.0000
V_fixture= 0.0
V_fixture_min= 0.0
V_fixture_max= 0.0
|time   V(typ)   V(min)   V(max)
0s        2.197nV    163nV      4.513nV
1.833ns   -655.1uV   -64.03nV   3.573mV
2.613ns   14.06mV    377.7nV    1.349V
3.04ns    320mV      -731.7uV   1.94V
3.501ns   769.7mV    -9.559mV   2.223V
4.711ns   1.589V     65.26mV    2.378V
5.926ns   1.824V     447.2mV    2.405V
7.823ns   1.887V     922.4mV    2.41V
11.26ns   1.899V     1.155V     2.41V
50ns      1.9V       1.181V     2.411V
[Falling Waveform]
R_fixture= 50.0000
V_fixture= 3.3000
V_fixture_min= 2.7000
V_fixture_max= 3.6000
|time   V(typ)   V(min)   V(max)
0s        3.3V       2.7V       3.6V
1.972ns   3.309V     2.7V       3.605V
2.773ns   3.301V     2.7V       2.41V
3.243ns   2.957V     2.709V     1.933V
3.872ns   2.448V     2.709V     1.577V
4.854ns   1.953V     2.623V     1.407V
6.074ns   1.687V     2.259V     1.373V
7.552ns   1.609V     1.943V     1.365V
11.04ns   1.587V     1.707V     1.363V
50ns      1.586V     1.682V     1.362V
[Falling Waveform]
R_fixture= 50.0000
V_fixture= 0.0
V_fixture_min= 0.0
V_fixture_max= 0.0
|time   V(typ)   V(min)   V(max)
0s        1.9V       1.181V     2.411V
1.459ns   1.9V       1.181V     2.325V
1.554ns   1.901V     1.181V     2.121V
1.969ns   1.81V      1.181V     429.5mV
2.323ns   1.003V     1.182V     1.459mV
2.634ns   327.3mV    1.181V     4.661mV
2.904ns   53.19mV    1.159V     2.581mV
3.973ns   2.055mV    208.9mV    1.243mV
4.73ns    1.403mV    7.204mV    827.9uV
50ns      243.8uV    184.2uV    263uV
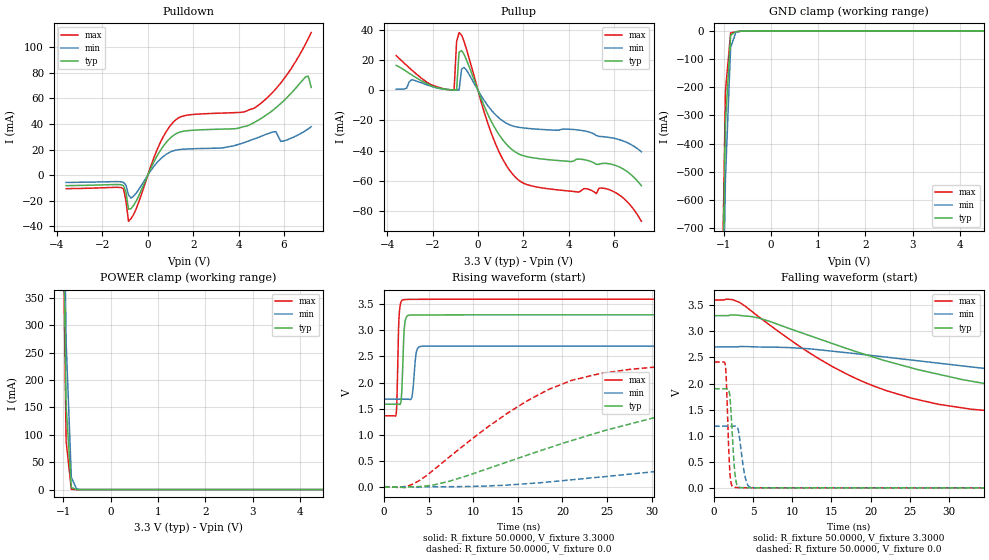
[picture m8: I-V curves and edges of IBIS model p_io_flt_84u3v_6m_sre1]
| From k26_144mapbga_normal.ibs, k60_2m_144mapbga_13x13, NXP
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[Model] p_io_flt_84u3v_6m_sre1
|   Model p_io_flt_84u3v_6m_sre1
| Library cells for typ/min/max conditions are connected as defined below:
|  pad - External Pad
|  ipp_do - Core Input
|  ipp_obe - Output Buffer Enable
|  esd_boost - vdd_s_3v
|  esd_bus - vdd_s_3v
|  ipp_do_3v - vss_bulk
|  ipp_ibe - vss_s_lv
|  ipp_ibe_3v - vss_bulk
|  ipp_ina40a_3v - NC
|  ipp_ina40b_3v - NC
|  ipp_ina_3v - NC
|  ipp_ind - NC
|  ipp_ind_3v - NC
|  ipp_obe1_3v - vss_bulk
|  ipp_pue - vss_s_lv
|  ipp_pue_3v - vss_bulk
|  ipp_pus - vss_s_lv
|  ipp_pus_3v - vss_bulk
|  ipp_sre - vdd_s_lv
|  ipp_sre_3v - vss_bulk
|  ipt_mode_sw_3v - vss_bulk
|  vdd_s_3v - vdd_s_3v
|  vdd_s_lv - vdd_s_lv
|  vss_bulk - vss_bulk
|  vss_s_lv - vss_s_lv
| All other pins connected to ground
Model_type I/O
Polarity   Non-Inverting
Enable   Active-High
Vinl =   1.1550V
Vinh =   2.3100V
Vmeas =  1.6500V
Cref =   25.0000pF
Rref =   50.0000
Vref =   0.0V
C_comp   2.2909pF   2.1249pF   2.5080pF
[Temperature Range]   25.0000   0.1250k   -40.0000
[Voltage Range]   3.3000V   2.7000V   3.6000V
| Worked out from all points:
|   slope of the pulldown table from 0 to 0.495 V, typ, clamps not added: 28.2 ohm
|   slope of the pullup table from 0 to 0.495 V, typ, clamps not added: 27.8 ohm
|   GND clamp passes 1 mA (typ) near -0.59 V on its own axis
|   POWER clamp passes 1 mA (typ) near -0.75 V on its own axis
|   rising waveform, R_fixture 50.0000, V_fixture 3.3000: 20-80 % time 223ps typ, 287ps min, 185ps max; typ from 1.58 V to 3.3 V
|   rising waveform, R_fixture 50.0000, V_fixture 0.0: 20-80 % time 23.8ns typ, 52.2ns min, 12.7ns max; typ from 0 V to 1.9 V
|   falling waveform, R_fixture 50.0000, V_fixture 3.3000: 20-80 % time 26.1ns typ, 44.9ns min, 16.4ns max; typ from 3.3 V to 1.58 V
|   falling waveform, R_fixture 50.0000, V_fixture 0.0: 20-80 % time 461ps typ, 662ps min, 346ps max; typ from 1.9 V to 0 V
[Pulldown]
|Voltage   I(typ)   I(min)   I(max)
-3.6V     -8.15mA    -5.66mA    -10.53mA
-1.07V    -8.198mA   -5.617mA   -10.68mA
-850mV    -26.62mA   -15.53mA   -35.97mA
-520mV    -20.5mA    -14.15mA   -26.68mA
470mV     16.86mA    11.06mA    22.3mA
1.13V     31.02mA    19.05mA    41.52mA
4.76V     41.79mA    28.7mA     53.11mA
5.64V     52.6mA     33.9mA     67.3mA
5.86V     55.9mA     26.3mA     71.9mA
6.96V     76.8mA     34.9mA     102.7mA
7.07V     77.1mA     36.1mA     106.5mA
7.2V      68.4mA     37.8mA     111.2mA
[Pullup]
|Voltage   I(typ)   I(min)   I(max)
-3.6V     16.4mA     700uA      22.9mA
-2.92V    10.2mA     6.9mA      13.4mA
-1.05V    150uA      153uA      179uA
-940mV    112uA      101uA      32.24mA
-830mV    25.23mA    69uA       38.16mA
-720mV    26.17mA    13.99mA    36.46mA
-610mV    23.71mA    15.08mA    32.29mA
600mV     -20.93mA   -13.37mA   -28.92mA
1.59V     -40.35mA   -23.94mA   -56.67mA
2.91V     -45.71mA   -26.1mA    -64.89mA
5.77V     -48.71mA   -31.24mA   -65.81mA
7.2V      -63.28mA   -40.8mA    -86.82mA
[GND_clamp]
|Voltage   I(typ)   I(min)   I(max)
-3.6V     -40.71A    -40.48A    -40.9A
-1.07V    -1.446A    -1.633A    -1.35A
-960mV    -327.7mA   -524.2mA   -214.8mA
-850mV    -15.52mA   -59.01mA   -7.646mA
-740mV    -3.054mA   -5.095mA   -3.462mA
-520mV    -339uA     -453.3uA   -279.9uA
7.2V      0A         0A         0A
[POWER_clamp]
|Voltage   I(typ)   I(min)   I(max)
-3.6V     26.65A     26.49A     26.81A
-1.05V    840.8mA    960.6mA    777.3mA
-940mV    152.6mA    269.8mA    87.83mA
-830mV    3.854mA    22.63mA    588.6uA
-720mV    55.07uA    1mA        2.492uA
-610mV    762.6nA    41.04uA    10.61nA
7.2V      0A         0A         0A
[Ramp]
| variable   typ   min   max
dV/dt_r  1.1400/23.8271n   0.7087/52.1647n   1.4468/12.6690n
dV/dt_f  1.0289/26.0593n   0.6111/44.8930n   1.3431/16.4117n
R_load = 50.0000
[Rising Waveform]
R_fixture= 50.0000
V_fixture= 3.3000
V_fixture_min= 2.7000
V_fixture_max= 3.6000
|time   V(typ)   V(min)   V(max)
0s        1.585V     1.681V     1.361V
1.366ns   1.585V     1.681V     1.389V
1.676ns   1.584V     1.681V     3.211V
1.919ns   1.639V     1.681V     3.549V
2.256ns   2.981V     1.682V     3.591V
2.578ns   3.271V     1.683V     3.594V
3.137ns   3.297V     1.715V     3.596V
3.711ns   3.297V     2.637V     3.596V
4.45ns    3.297V     2.698V     3.597V
300ns     3.3V       2.7V       3.6V
[Rising Waveform]
R_fixture= 50.0000
V_fixture= 0.0
V_fixture_min= 0.0
V_fixture_max= 0.0
|time   V(typ)   V(min)   V(max)
0s        2.197nV    163nV      4.513nV
4.039ns   5.618mV    -3.204mV   128.2mV
13.62ns   467.9mV    32.02mV    1.389V
18.42ns   743.2mV    92.7mV     1.865V
24.2ns    1.052V     186.8mV    2.172V
34.45ns   1.468V     361.6mV    2.339V
53.69ns   1.8V       666.2mV    2.402V
83.97ns   1.886V     985.6mV    2.41V
113.3ns   1.898V     1.113V     2.411V
300ns     1.9V       1.181V     2.411V
[Falling Waveform]
R_fixture= 50.0000
V_fixture= 3.3000
V_fixture_min= 2.7000
V_fixture_max= 3.6000
|time   V(typ)   V(min)   V(max)
0s        3.3V       2.7V       3.6V
3.238ns   3.305V     2.709V     3.555V
5.732ns   3.254V     2.7V       3.276V
13.09ns   2.87V      2.652V     2.502V
20.35ns   2.507V     2.534V     1.955V
28.66ns   2.179V     2.39V      1.602V
37.51ns   1.928V     2.242V     1.446V
57.12ns   1.67V      1.98V      1.374V
100.1ns   1.59V      1.731V     1.361V
300ns     1.585V     1.681V     1.361V
[Falling Waveform]
R_fixture= 50.0000
V_fixture= 0.0
V_fixture_min= 0.0
V_fixture_max= 0.0
|time   V(typ)   V(min)   V(max)
0s        1.9V       1.181V     2.411V
1.412ns   1.9V       1.181V     2.372V
1.551ns   1.901V     1.181V     2.124V
1.89ns    1.873V     1.181V     667.5mV
2.2ns     1.361V     1.181V     71.79mV
2.633ns   326.6mV    1.185V     10.63mV
3.06ns    23.18mV    1.121V     3.738mV
4.083ns   2.496mV    142.2mV    2.652mV
5.247ns   2.07mV     2.277mV    1.751mV
300ns     -59.37nV   3.03uV     1.767uV
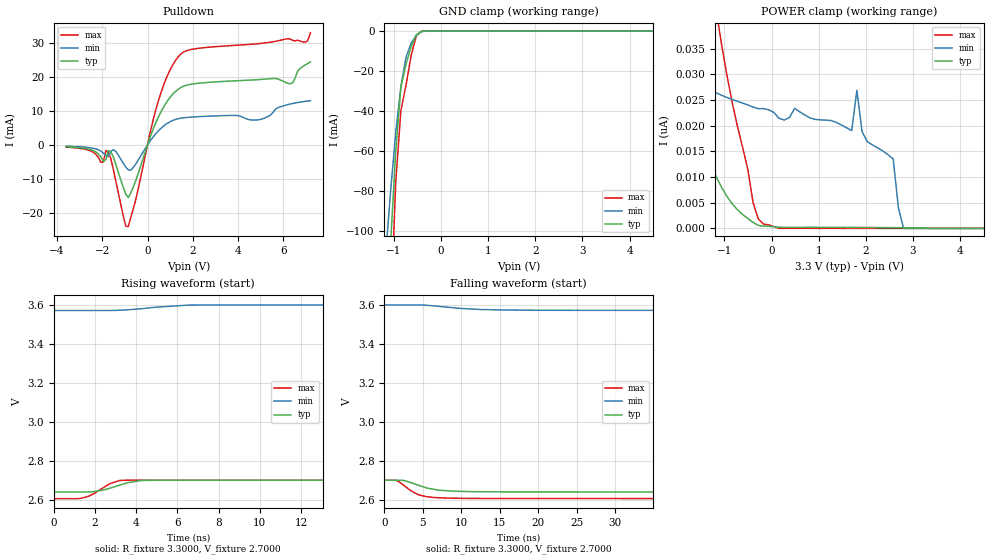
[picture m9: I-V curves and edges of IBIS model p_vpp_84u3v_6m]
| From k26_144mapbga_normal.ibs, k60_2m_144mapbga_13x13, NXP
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[Model] p_vpp_84u3v_6m
|   Model p_vpp_84u3v_6m
| Library cells for typ/min/max conditions are connected as defined below:
|  pad - External Pad
|  ipp_do - Core Input
|  ipp_obe - Output Buffer Enable
|  esd_boost - vdd_s_3v
|  esd_bus - vdd_s_3v
|  ipp_ina_hv - NC
|  ipp_ind - NC
|  ipp_ind_3v - NC
|  vdd_s_3v - vdd_s_3v
|  vdd_s_lv - vdd_s_lv
|  vpp1 - NC
|  vpp2 - NC
|  vss_bulk - vss_bulk
|  vss_s_lv - vss_s_lv
| All other pins connected to ground
Model_type I/O_open_drain
Polarity   Non-Inverting
Enable   Active-High
Vinl =   1.1550V
Vinh =   2.3100V
Vmeas =  1.6500V
Cref =   25.0000pF
Rref =   50.0000
Vref =   0.0V
C_comp   5.1669pF   5.0106pF   5.1706pF
[Temperature Range]   25.0000   0.1250k   -40.0000
[Voltage Range]   3.3000V   2.7000V   3.6000V
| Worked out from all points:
|   slope of the pulldown table from 0 to 0.495 V, typ, clamps not added: 58.6 ohm
|   GND clamp passes 1 mA (typ) near -0.47 V on its own axis
|   rising waveform, R_fixture 3.3000, V_fixture 2.7000: 20-80 % time 1.16ns typ, NA min, 892ps max; typ from 2.64 V to 2.7 V
|   falling waveform, R_fixture 3.3000, V_fixture 2.7000: 20-80 % time 3.29ns typ, NA min, 2.27ns max; typ from 2.7 V to 2.64 V
[Pulldown]
|Voltage   I(typ)   I(min)   I(max)
-3.6V     -550uA     -370uA     -650uA
-1.95V    -4.844mA   -2.425mA   -4.985mA
-1.73V    -1.652mA   -3.49mA    -2.281mA
-1.51V    -3.526mA   -1.389mA   -7.241mA
-960mV    -14.51mA   -6.53mA    -23.92mA
-850mV    -15.5mA    -7.348mA   -24.07mA
470mV     8.1mA      4.077mA    12.78mA
1.46V     16.88mA    7.868mA    26.73mA
4.87V     19.24mA    7.382mA    29.83mA
6.3V      18.03mA    12.04mA    31.22mA
6.96V     23.54mA    12.84mA    30.29mA
7.2V      24.46mA    13.04mA    33.05mA
[GND_clamp]
|Voltage   I(typ)   I(min)   I(max)
-3.6V     -20.39A    -20.77A    -20.23A
-1.18V    -159.2mA   -114.4mA   -222.3mA
-1.07V    -107.4mA   -80.64mA   -145.7mA
-960mV    -60.3mA    -51.09mA   -75.84mA
-850mV    -28.19mA   -27.76mA   -39.8mA
-740mV    -16.35mA   -13.01mA   -26.85mA
-630mV    -7.667mA   -5.929mA   -12.01mA
-520mV    -1.873mA   -2.074mA   -2.259mA
-410mV    -107uA     -347.7uA   -45.9uA
-190mV    -74.15nA   -1.752uA   -4.182nA
7.2V      0A         0A         0A
[POWER_clamp]
|Voltage   I(typ)   I(min)   I(max)
-3.6V     150.5nA    136nA      328.6nA
-2.37V    55.44nA    39.04nA    150.4nA
-2.04V    38.31nA    33.31nA    113.9nA
-1.16V    9.824nA    26.31nA    41.67nA
-280mV    573.7pA    23.29nA    1.837nA
1.7V      183.9pA    19.02nA    4.727pA
1.81V     177.9pA    26.87nA    4.198pA
1.92V     173pA      18.82nA    3.672pA
2.03V     168.2pA    16.9nA     3.146pA
2.58V     145.3pA    13.51nA    489.2fA
2.8V      128.4pA    0A         0A
7.2V      0A         0A         0A
[Ramp]
| variable   typ   min   max
dV/dt_r  0.5481/1.2077n   0.2505/1.8119n   0.8525/0.9365n
dV/dt_f  0.5443/3.1864n   0.2504/5.4376n   0.8524/2.3068n
R_load = 50.0000
[Rising Waveform]
R_fixture= 3.3000
V_fixture= 2.7000
V_fixture_min= 3.6000
|time   V(typ)   V(min)   V(max)
0s        2.639V     3.571V     2.605V
1.431ns   2.639V     3.571V     2.61V
1.934ns   2.642V     3.571V     2.631V
2.734ns   2.66V      3.571V     2.683V
3.215ns   2.675V     3.573V     2.699V
3.815ns   2.691V     3.577V     2.701V
4.307ns   2.699V     3.581V     2.7V
6.523ns   2.7V       3.599V     2.7V
7.632ns   2.7V       3.6V       2.7V
350ns     2.7V       3.6V       2.7V
[Falling Waveform]
R_fixture= 3.3000
V_fixture= 2.7000
V_fixture_min= 3.6000
|time   V(typ)   V(min)   V(max)
0s        2.7V       3.6V       2.7V
1.602ns   2.7V       3.6V       2.698V
2.573ns   2.698V     3.6V       2.672V
3.463ns   2.688V     3.6V       2.646V
4.436ns   2.674V     3.6V       2.625V
5.459ns   2.661V     3.598V     2.615V
7.154ns   2.648V     3.592V     2.61V
10.72ns   2.642V     3.58V      2.607V
24.63ns   2.64V      3.572V     2.606V
350ns     2.639V     3.572V     2.605V
